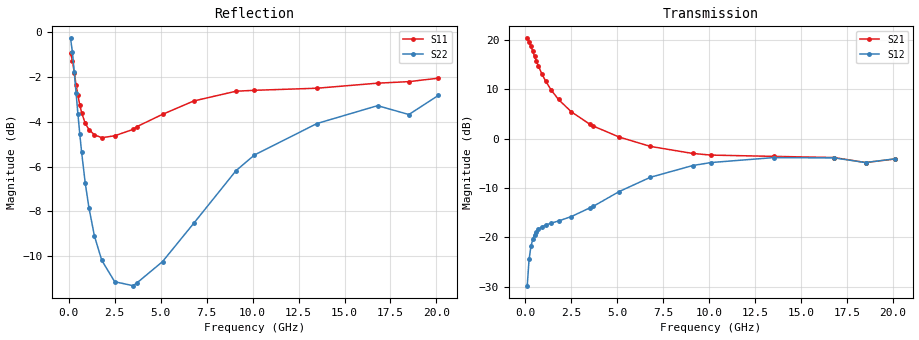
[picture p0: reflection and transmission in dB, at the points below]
!  Infineon Technologies AG
! BFR380L3 , PF131585-7, No.6, Th 09.10.01, soldered on pcb-board, measured with PP GSG850
!  Vce=1.75 V,  Ic=3.0 mA
! Common Emitter S-Parameters:  15. November 2001
#  GHz  S  MA  R  50
! f  S11  S21  S12  S22
! GHz  Mag  Ang  Mag  Ang  Mag  Ang  Mag  Ang
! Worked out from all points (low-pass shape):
!   201 points, 100 MHz to 20.1 GHz, reference 50 ohm
!   highest |S21| = 20.35 dB at 100 MHz (marker M1); lowest = -4.8 dB at 18.5 GHz (marker M2)
!   |S21| within 3 dB of the highest: start of sweep to 436.3 MHz
!   lowest |S11| = -4.7 dB at 1.8 GHz (marker M3), VSWR 3.78, Z = 13.3 - j4.06 ohm
!   |S11| at or under -10 dB: nowhere
!   |S22| runs from -11.4 to -0.3 dB; largest |S21 - S12| = 10
!   S11 on the Smith chart (normalised r, x): 100 MHz: 1.37, -4.76; 400 MHz: 0.33, -1.18; 1.1 GHz: 0.27, -0.33; 3.7 GHz: 0.26, +0.27; 9.1 GHz: 0.33, +1.06; 20.1 GHz: 0.97, +2.54
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0.1  0.8978 -22.0  10.42 164.7  0.03224 76.2  0.9701 -13.1
0.2  0.8655 -43.6  9.547 151.1  0.05976 66.7  0.9029 -24.9
0.3  0.8134 -62.5  8.633 139.3  0.0807 57.5  0.816 -34.6
0.4  0.7624 -78.2  7.695 129.5  0.09568 50.6  0.7315 -42.3
0.5  0.7235 -91.6  6.842 121.5  0.1065 45.5  0.6564 -48.3
0.6  0.6883 -103.2  6.105 114.8  0.1142 41.7  0.5928 -53.0
0.7  0.6613 -113.0  5.494 109.0  0.1199 38.9  0.5399 -56.8
0.9  0.6258 -128.7  4.525 99.9  0.1277 35.4  0.4595 -62.6
1.1  0.6065 -141.3  3.843 92.5  0.1332 33.5  0.4053 -67.1
1.4  0.59 -155.5  3.118 83.4  0.1388 32.9  0.3501 -72.3
1.8  0.5817 -170.0  2.498 73.5  0.1463 34.0  0.309 -78.4
2.5  0.5874 171.0  1.872 59.4  0.1621 38.2  0.277 -89.7
3.5  0.607 150.8  1.403 43.1  0.1984 44.2  0.2714 -107.7
3.7  0.6155 147.8  1.341 40.6  0.2063 44.8  0.2751 -112.4
5.1  0.656 126.1  1.039 23.5  0.2908 45.5  0.3072 -139.9
6.8  0.7028 105.1  0.8348 9.6  0.4059 37.7  0.3743 -173.8
9.1  0.7389 84.0  0.708 -1.7  0.534 21.3  0.4909 150.5
10.1  0.7424 76.5  0.6815 -5.6  0.5728 13.9  0.532 137.0
13.5  0.7504 58.7  0.6616 -19.2  0.6428 -9.3  0.6256 101.8
16.8  0.7702 46.9  0.6434 -31.1  0.6383 -26.0  0.686 78.0
18.5  0.7763 45.3  0.573 -38.9  0.5724 -34.6  0.6553 72.0
20.1  0.7902 38.4  0.6219 -42.4  0.625 -39.7  0.723 61.0
